VERSION 5.8 ;
BUSBITCHARS "[]" ;
DIVIDERCHAR "/" ;
UNITS
    DATABASE MICRONS 1000 ;
END UNITS

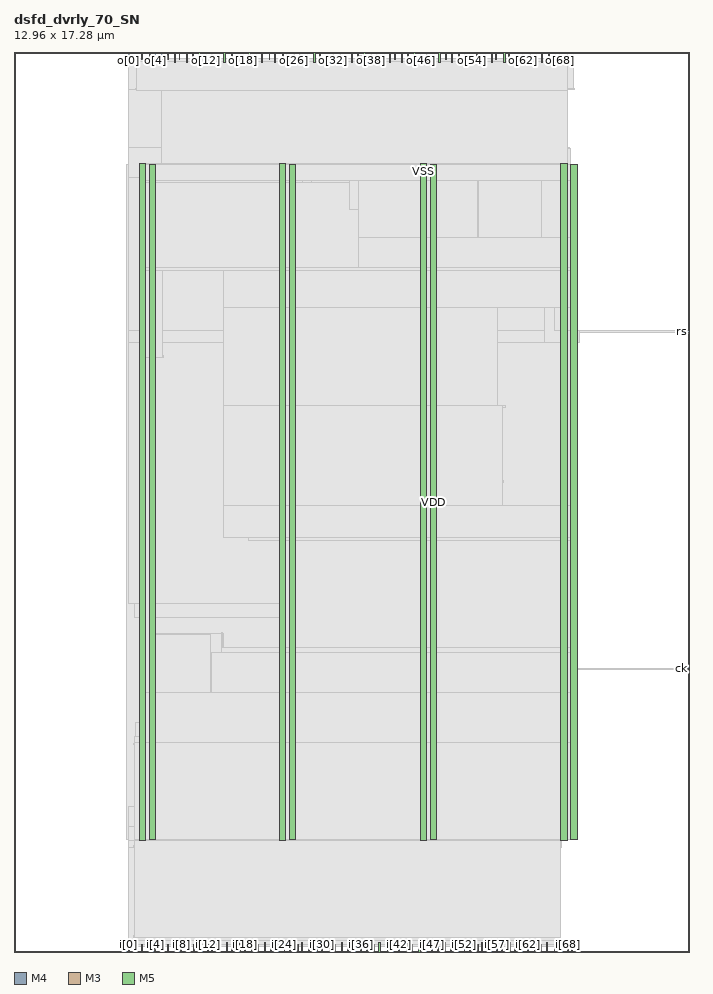
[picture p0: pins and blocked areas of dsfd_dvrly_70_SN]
MACRO dsfd_dvrly_70_SN
  FOREIGN dsfd_dvrly_70_SN 0 0 ;
  CLASS BLOCK ;
  SIZE 12.96 BY 17.28 ;
  PIN ck
    DIRECTION INPUT ;
    USE SIGNAL ;
    PORT
      LAYER M4 ;
        RECT  12.768 5.424 12.96 5.448 ;
    END
  END ck
  PIN ck_o
    DIRECTION OUTPUT ;
    USE SIGNAL ;
    PORT
      LAYER M3 ;
        RECT  10.728 17.136 10.746 17.28 ;
    END
  END ck_o
  PIN i[0]
    DIRECTION INPUT ;
    USE SIGNAL ;
    PORT
      LAYER M3 ;
        RECT  2.196 0 2.214 0.144 ;
    END
  END i[0]
  PIN i[10]
    DIRECTION INPUT ;
    USE SIGNAL ;
    PORT
      LAYER M3 ;
        RECT  3.456 0 3.474 0.144 ;
    END
  END i[10]
  PIN i[11]
    DIRECTION INPUT ;
    USE SIGNAL ;
    PORT
      LAYER M5 ;
        RECT  3.552 0 3.576 0.192 ;
    END
  END i[11]
  PIN i[12]
    DIRECTION INPUT ;
    USE SIGNAL ;
    PORT
      LAYER M3 ;
        RECT  3.708 0 3.726 0.144 ;
    END
  END i[12]
  PIN i[13]
    DIRECTION INPUT ;
    USE SIGNAL ;
    PORT
      LAYER M5 ;
        RECT  3.792 0 3.816 0.192 ;
    END
  END i[13]
  PIN i[14]
    DIRECTION INPUT ;
    USE SIGNAL ;
    PORT
      LAYER M3 ;
        RECT  3.924 0 3.942 0.144 ;
    END
  END i[14]
  PIN i[15]
    DIRECTION INPUT ;
    USE SIGNAL ;
    PORT
      LAYER M5 ;
        RECT  4.08 0 4.104 0.192 ;
    END
  END i[15]
  PIN i[16]
    DIRECTION INPUT ;
    USE SIGNAL ;
    PORT
      LAYER M3 ;
        RECT  4.176 0 4.194 0.144 ;
    END
  END i[16]
  PIN i[17]
    DIRECTION INPUT ;
    USE SIGNAL ;
    PORT
      LAYER M5 ;
        RECT  4.32 0 4.344 0.192 ;
    END
  END i[17]
  PIN i[18]
    DIRECTION INPUT ;
    USE SIGNAL ;
    PORT
      LAYER M3 ;
        RECT  4.428 0 4.446 0.144 ;
    END
  END i[18]
  PIN i[19]
    DIRECTION INPUT ;
    USE SIGNAL ;
    PORT
      LAYER M5 ;
        RECT  4.56 0 4.584 0.192 ;
    END
  END i[19]
  PIN i[1]
    DIRECTION INPUT ;
    USE SIGNAL ;
    PORT
      LAYER M5 ;
        RECT  2.352 0 2.376 0.192 ;
    END
  END i[1]
  PIN i[20]
    DIRECTION INPUT ;
    USE SIGNAL ;
    PORT
      LAYER M3 ;
        RECT  4.68 0 4.698 0.144 ;
    END
  END i[20]
  PIN i[21]
    DIRECTION INPUT ;
    USE SIGNAL ;
    PORT
      LAYER M5 ;
        RECT  4.8 0 4.824 0.192 ;
    END
  END i[21]
  PIN i[22]
    DIRECTION INPUT ;
    USE SIGNAL ;
    PORT
      LAYER M3 ;
        RECT  4.932 0 4.95 0.144 ;
    END
  END i[22]
  PIN i[23]
    DIRECTION INPUT ;
    USE SIGNAL ;
    PORT
      LAYER M5 ;
        RECT  5.04 0 5.064 0.192 ;
    END
  END i[23]
  PIN i[24]
    DIRECTION INPUT ;
    USE SIGNAL ;
    PORT
      LAYER M3 ;
        RECT  5.184 0 5.202 0.144 ;
    END
  END i[24]
  PIN i[25]
    DIRECTION INPUT ;
    USE SIGNAL ;
    PORT
      LAYER M5 ;
        RECT  5.28 0 5.304 0.192 ;
    END
  END i[25]
  PIN i[26]
    DIRECTION INPUT ;
    USE SIGNAL ;
    PORT
      LAYER M3 ;
        RECT  5.436 0 5.454 0.144 ;
    END
  END i[26]
  PIN i[27]
    DIRECTION INPUT ;
    USE SIGNAL ;
    PORT
      LAYER M5 ;
        RECT  5.52 0 5.544 0.192 ;
    END
  END i[27]
  PIN i[28]
    DIRECTION INPUT ;
    USE SIGNAL ;
    PORT
      LAYER M3 ;
        RECT  5.652 0 5.67 0.144 ;
    END
  END i[28]
  PIN i[29]
    DIRECTION INPUT ;
    USE SIGNAL ;
    PORT
      LAYER M5 ;
        RECT  5.808 0 5.832 0.192 ;
    END
  END i[29]
  PIN i[2]
    DIRECTION INPUT ;
    USE SIGNAL ;
    PORT
      LAYER M3 ;
        RECT  2.448 0 2.466 0.144 ;
    END
  END i[2]
  PIN i[30]
    DIRECTION INPUT ;
    USE SIGNAL ;
    PORT
      LAYER M3 ;
        RECT  5.904 0 5.922 0.144 ;
    END
  END i[30]
  PIN i[31]
    DIRECTION INPUT ;
    USE SIGNAL ;
    PORT
      LAYER M5 ;
        RECT  6.048 0 6.072 0.192 ;
    END
  END i[31]
  PIN i[32]
    DIRECTION INPUT ;
    USE SIGNAL ;
    PORT
      LAYER M3 ;
        RECT  6.156 0 6.174 0.144 ;
    END
  END i[32]
  PIN i[33]
    DIRECTION INPUT ;
    USE SIGNAL ;
    PORT
      LAYER M5 ;
        RECT  6.288 0 6.312 0.192 ;
    END
  END i[33]
  PIN i[34]
    DIRECTION INPUT ;
    USE SIGNAL ;
    PORT
      LAYER M3 ;
        RECT  6.408 0 6.426 0.144 ;
    END
  END i[34]
  PIN i[35]
    DIRECTION INPUT ;
    USE SIGNAL ;
    PORT
      LAYER M5 ;
        RECT  6.528 0 6.552 0.192 ;
    END
  END i[35]
  PIN i[36]
    DIRECTION INPUT ;
    USE SIGNAL ;
    PORT
      LAYER M3 ;
        RECT  6.66 0 6.678 0.144 ;
    END
  END i[36]
  PIN i[37]
    DIRECTION INPUT ;
    USE SIGNAL ;
    PORT
      LAYER M5 ;
        RECT  6.768 0 6.792 0.192 ;
    END
  END i[37]
  PIN i[38]
    DIRECTION INPUT ;
    USE SIGNAL ;
    PORT
      LAYER M3 ;
        RECT  6.912 0 6.93 0.144 ;
    END
  END i[38]
  PIN i[39]
    DIRECTION INPUT ;
    USE SIGNAL ;
    PORT
      LAYER M5 ;
        RECT  7.008 0 7.032 0.192 ;
    END
  END i[39]
  PIN i[3]
    DIRECTION INPUT ;
    USE SIGNAL ;
    PORT
      LAYER M5 ;
        RECT  2.592 0 2.616 0.192 ;
    END
  END i[3]
  PIN i[40]
    DIRECTION INPUT ;
    USE SIGNAL ;
    PORT
      LAYER M3 ;
        RECT  7.164 0 7.182 0.144 ;
    END
  END i[40]
  PIN i[41]
    DIRECTION INPUT ;
    USE SIGNAL ;
    PORT
      LAYER M5 ;
        RECT  7.248 0 7.272 0.192 ;
    END
  END i[41]
  PIN i[42]
    DIRECTION INPUT ;
    USE SIGNAL ;
    PORT
      LAYER M3 ;
        RECT  7.38 0 7.398 0.144 ;
    END
  END i[42]
  PIN i[43]
    DIRECTION INPUT ;
    USE SIGNAL ;
    PORT
      LAYER M5 ;
        RECT  7.536 0 7.56 0.192 ;
    END
  END i[43]
  PIN i[44]
    DIRECTION INPUT ;
    USE SIGNAL ;
    PORT
      LAYER M3 ;
        RECT  7.632 0 7.65 0.144 ;
    END
  END i[44]
  PIN i[45]
    DIRECTION INPUT ;
    USE SIGNAL ;
    PORT
      LAYER M5 ;
        RECT  7.776 0 7.8 0.192 ;
    END
  END i[45]
  PIN i[46]
    DIRECTION INPUT ;
    USE SIGNAL ;
    PORT
      LAYER M3 ;
        RECT  7.884 0 7.902 0.144 ;
    END
  END i[46]
  PIN i[47]
    DIRECTION INPUT ;
    USE SIGNAL ;
    PORT
      LAYER M5 ;
        RECT  8.016 0 8.04 0.192 ;
    END
  END i[47]
  PIN i[48]
    DIRECTION INPUT ;
    USE SIGNAL ;
    PORT
      LAYER M3 ;
        RECT  8.136 0 8.154 0.144 ;
    END
  END i[48]
  PIN i[49]
    DIRECTION INPUT ;
    USE SIGNAL ;
    PORT
      LAYER M5 ;
        RECT  8.256 0 8.28 0.192 ;
    END
  END i[49]
  PIN i[4]
    DIRECTION INPUT ;
    USE SIGNAL ;
    PORT
      LAYER M3 ;
        RECT  2.7 0 2.718 0.144 ;
    END
  END i[4]
  PIN i[50]
    DIRECTION INPUT ;
    USE SIGNAL ;
    PORT
      LAYER M3 ;
        RECT  8.388 0 8.406 0.144 ;
    END
  END i[50]
  PIN i[51]
    DIRECTION INPUT ;
    USE SIGNAL ;
    PORT
      LAYER M5 ;
        RECT  8.496 0 8.52 0.192 ;
    END
  END i[51]
  PIN i[52]
    DIRECTION INPUT ;
    USE SIGNAL ;
    PORT
      LAYER M3 ;
        RECT  8.64 0 8.658 0.144 ;
    END
  END i[52]
  PIN i[53]
    DIRECTION INPUT ;
    USE SIGNAL ;
    PORT
      LAYER M5 ;
        RECT  8.736 0 8.76 0.192 ;
    END
  END i[53]
  PIN i[54]
    DIRECTION INPUT ;
    USE SIGNAL ;
    PORT
      LAYER M3 ;
        RECT  8.892 0 8.91 0.144 ;
    END
  END i[54]
  PIN i[55]
    DIRECTION INPUT ;
    USE SIGNAL ;
    PORT
      LAYER M5 ;
        RECT  8.976 0 9 0.192 ;
    END
  END i[55]
  PIN i[56]
    DIRECTION INPUT ;
    USE SIGNAL ;
    PORT
      LAYER M3 ;
        RECT  9.108 0 9.126 0.144 ;
    END
  END i[56]
  PIN i[57]
    DIRECTION INPUT ;
    USE SIGNAL ;
    PORT
      LAYER M5 ;
        RECT  9.264 0 9.288 0.192 ;
    END
  END i[57]
  PIN i[58]
    DIRECTION INPUT ;
    USE SIGNAL ;
    PORT
      LAYER M3 ;
        RECT  9.36 0 9.378 0.144 ;
    END
  END i[58]
  PIN i[59]
    DIRECTION INPUT ;
    USE SIGNAL ;
    PORT
      LAYER M5 ;
        RECT  9.504 0 9.528 0.192 ;
    END
  END i[59]
  PIN i[5]
    DIRECTION INPUT ;
    USE SIGNAL ;
    PORT
      LAYER M5 ;
        RECT  2.832 0 2.856 0.192 ;
    END
  END i[5]
  PIN i[60]
    DIRECTION INPUT ;
    USE SIGNAL ;
    PORT
      LAYER M3 ;
        RECT  9.612 0 9.63 0.144 ;
    END
  END i[60]
  PIN i[61]
    DIRECTION INPUT ;
    USE SIGNAL ;
    PORT
      LAYER M5 ;
        RECT  9.744 0 9.768 0.192 ;
    END
  END i[61]
  PIN i[62]
    DIRECTION INPUT ;
    USE SIGNAL ;
    PORT
      LAYER M3 ;
        RECT  9.864 0 9.882 0.144 ;
    END
  END i[62]
  PIN i[63]
    DIRECTION INPUT ;
    USE SIGNAL ;
    PORT
      LAYER M5 ;
        RECT  9.984 0 10.008 0.192 ;
    END
  END i[63]
  PIN i[64]
    DIRECTION INPUT ;
    USE SIGNAL ;
    PORT
      LAYER M3 ;
        RECT  10.116 0 10.134 0.144 ;
    END
  END i[64]
  PIN i[65]
    DIRECTION INPUT ;
    USE SIGNAL ;
    PORT
      LAYER M5 ;
        RECT  10.224 0 10.248 0.192 ;
    END
  END i[65]
  PIN i[66]
    DIRECTION INPUT ;
    USE SIGNAL ;
    PORT
      LAYER M3 ;
        RECT  10.368 0 10.386 0.144 ;
    END
  END i[66]
  PIN i[67]
    DIRECTION INPUT ;
    USE SIGNAL ;
    PORT
      LAYER M5 ;
        RECT  10.464 0 10.488 0.192 ;
    END
  END i[67]
  PIN i[68]
    DIRECTION INPUT ;
    USE SIGNAL ;
    PORT
      LAYER M3 ;
        RECT  10.62 0 10.638 0.144 ;
    END
  END i[68]
  PIN i[69]
    DIRECTION INPUT ;
    USE SIGNAL ;
    PORT
      LAYER M5 ;
        RECT  10.704 0 10.728 0.192 ;
    END
  END i[69]
  PIN i[6]
    DIRECTION INPUT ;
    USE SIGNAL ;
    PORT
      LAYER M3 ;
        RECT  2.952 0 2.97 0.144 ;
    END
  END i[6]
  PIN i[7]
    DIRECTION INPUT ;
    USE SIGNAL ;
    PORT
      LAYER M5 ;
        RECT  3.072 0 3.096 0.192 ;
    END
  END i[7]
  PIN i[8]
    DIRECTION INPUT ;
    USE SIGNAL ;
    PORT
      LAYER M3 ;
        RECT  3.204 0 3.222 0.144 ;
    END
  END i[8]
  PIN i[9]
    DIRECTION INPUT ;
    USE SIGNAL ;
    PORT
      LAYER M5 ;
        RECT  3.312 0 3.336 0.192 ;
    END
  END i[9]
  PIN o[0]
    DIRECTION OUTPUT ;
    USE SIGNAL ;
    PORT
      LAYER M3 ;
        RECT  2.196 17.136 2.214 17.28 ;
    END
  END o[0]
  PIN o[10]
    DIRECTION OUTPUT ;
    USE SIGNAL ;
    PORT
      LAYER M3 ;
        RECT  3.42 17.136 3.438 17.28 ;
    END
  END o[10]
  PIN o[11]
    DIRECTION OUTPUT ;
    USE SIGNAL ;
    PORT
      LAYER M5 ;
        RECT  3.552 17.088 3.576 17.28 ;
    END
  END o[11]
  PIN o[12]
    DIRECTION OUTPUT ;
    USE SIGNAL ;
    PORT
      LAYER M3 ;
        RECT  3.672 17.136 3.69 17.28 ;
    END
  END o[12]
  PIN o[13]
    DIRECTION OUTPUT ;
    USE SIGNAL ;
    PORT
      LAYER M5 ;
        RECT  3.792 17.088 3.816 17.28 ;
    END
  END o[13]
  PIN o[14]
    DIRECTION OUTPUT ;
    USE SIGNAL ;
    PORT
      LAYER M3 ;
        RECT  3.924 17.136 3.942 17.28 ;
    END
  END o[14]
  PIN o[15]
    DIRECTION OUTPUT ;
    USE SIGNAL ;
    PORT
      LAYER M5 ;
        RECT  4.032 17.088 4.056 17.28 ;
    END
  END o[15]
  PIN o[16]
    DIRECTION OUTPUT ;
    USE SIGNAL ;
    PORT
      LAYER M3 ;
        RECT  4.176 17.136 4.194 17.28 ;
    END
  END o[16]
  PIN o[17]
    DIRECTION OUTPUT ;
    USE SIGNAL ;
    PORT
      LAYER M5 ;
        RECT  4.272 17.088 4.296 17.28 ;
    END
  END o[17]
  PIN o[18]
    DIRECTION OUTPUT ;
    USE SIGNAL ;
    PORT
      LAYER M3 ;
        RECT  4.392 17.136 4.41 17.28 ;
    END
  END o[18]
  PIN o[19]
    DIRECTION OUTPUT ;
    USE SIGNAL ;
    PORT
      LAYER M5 ;
        RECT  4.512 17.088 4.536 17.28 ;
    END
  END o[19]
  PIN o[1]
    DIRECTION OUTPUT ;
    USE SIGNAL ;
    PORT
      LAYER M5 ;
        RECT  2.352 17.088 2.376 17.28 ;
    END
  END o[1]
  PIN o[20]
    DIRECTION OUTPUT ;
    USE SIGNAL ;
    PORT
      LAYER M3 ;
        RECT  4.644 17.136 4.662 17.28 ;
    END
  END o[20]
  PIN o[21]
    DIRECTION OUTPUT ;
    USE SIGNAL ;
    PORT
      LAYER M5 ;
        RECT  4.752 17.088 4.776 17.28 ;
    END
  END o[21]
  PIN o[22]
    DIRECTION OUTPUT ;
    USE SIGNAL ;
    PORT
      LAYER M3 ;
        RECT  4.896 17.136 4.914 17.28 ;
    END
  END o[22]
  PIN o[23]
    DIRECTION OUTPUT ;
    USE SIGNAL ;
    PORT
      LAYER M5 ;
        RECT  4.992 17.088 5.016 17.28 ;
    END
  END o[23]
  PIN o[24]
    DIRECTION OUTPUT ;
    USE SIGNAL ;
    PORT
      LAYER M3 ;
        RECT  5.148 17.136 5.166 17.28 ;
    END
  END o[24]
  PIN o[25]
    DIRECTION OUTPUT ;
    USE SIGNAL ;
    PORT
      LAYER M5 ;
        RECT  5.232 17.088 5.256 17.28 ;
    END
  END o[25]
  PIN o[26]
    DIRECTION OUTPUT ;
    USE SIGNAL ;
    PORT
      LAYER M3 ;
        RECT  5.364 17.136 5.382 17.28 ;
    END
  END o[26]
  PIN o[27]
    DIRECTION OUTPUT ;
    USE SIGNAL ;
    PORT
      LAYER M5 ;
        RECT  5.472 17.088 5.496 17.28 ;
    END
  END o[27]
  PIN o[28]
    DIRECTION OUTPUT ;
    USE SIGNAL ;
    PORT
      LAYER M3 ;
        RECT  5.616 17.136 5.634 17.28 ;
    END
  END o[28]
  PIN o[29]
    DIRECTION OUTPUT ;
    USE SIGNAL ;
    PORT
      LAYER M5 ;
        RECT  5.76 17.088 5.784 17.28 ;
    END
  END o[29]
  PIN o[2]
    DIRECTION OUTPUT ;
    USE SIGNAL ;
    PORT
      LAYER M3 ;
        RECT  2.448 17.136 2.466 17.28 ;
    END
  END o[2]
  PIN o[30]
    DIRECTION OUTPUT ;
    USE SIGNAL ;
    PORT
      LAYER M3 ;
        RECT  5.868 17.136 5.886 17.28 ;
    END
  END o[30]
  PIN o[31]
    DIRECTION OUTPUT ;
    USE SIGNAL ;
    PORT
      LAYER M5 ;
        RECT  6 17.088 6.024 17.28 ;
    END
  END o[31]
  PIN o[32]
    DIRECTION OUTPUT ;
    USE SIGNAL ;
    PORT
      LAYER M3 ;
        RECT  6.12 17.136 6.138 17.28 ;
    END
  END o[32]
  PIN o[33]
    DIRECTION OUTPUT ;
    USE SIGNAL ;
    PORT
      LAYER M5 ;
        RECT  6.24 17.088 6.264 17.28 ;
    END
  END o[33]
  PIN o[34]
    DIRECTION OUTPUT ;
    USE SIGNAL ;
    PORT
      LAYER M3 ;
        RECT  6.336 17.136 6.354 17.28 ;
    END
  END o[34]
  PIN o[35]
    DIRECTION OUTPUT ;
    USE SIGNAL ;
    PORT
      LAYER M5 ;
        RECT  6.48 17.088 6.504 17.28 ;
    END
  END o[35]
  PIN o[36]
    DIRECTION OUTPUT ;
    USE SIGNAL ;
    PORT
      LAYER M3 ;
        RECT  6.588 17.136 6.606 17.28 ;
    END
  END o[36]
  PIN o[37]
    DIRECTION OUTPUT ;
    USE SIGNAL ;
    PORT
      LAYER M5 ;
        RECT  6.72 17.088 6.744 17.28 ;
    END
  END o[37]
  PIN o[38]
    DIRECTION OUTPUT ;
    USE SIGNAL ;
    PORT
      LAYER M3 ;
        RECT  6.84 17.136 6.858 17.28 ;
    END
  END o[38]
  PIN o[39]
    DIRECTION OUTPUT ;
    USE SIGNAL ;
    PORT
      LAYER M5 ;
        RECT  6.96 17.088 6.984 17.28 ;
    END
  END o[39]
  PIN o[3]
    DIRECTION OUTPUT ;
    USE SIGNAL ;
    PORT
      LAYER M5 ;
        RECT  2.592 17.088 2.616 17.28 ;
    END
  END o[3]
  PIN o[40]
    DIRECTION OUTPUT ;
    USE SIGNAL ;
    PORT
      LAYER M3 ;
        RECT  7.092 17.136 7.11 17.28 ;
    END
  END o[40]
  PIN o[41]
    DIRECTION OUTPUT ;
    USE SIGNAL ;
    PORT
      LAYER M5 ;
        RECT  7.2 17.088 7.224 17.28 ;
    END
  END o[41]
  PIN o[42]
    DIRECTION OUTPUT ;
    USE SIGNAL ;
    PORT
      LAYER M3 ;
        RECT  7.308 17.136 7.326 17.28 ;
    END
  END o[42]
  PIN o[43]
    DIRECTION OUTPUT ;
    USE SIGNAL ;
    PORT
      LAYER M5 ;
        RECT  7.44 17.088 7.464 17.28 ;
    END
  END o[43]
  PIN o[44]
    DIRECTION OUTPUT ;
    USE SIGNAL ;
    PORT
      LAYER M3 ;
        RECT  7.56 17.136 7.578 17.28 ;
    END
  END o[44]
  PIN o[45]
    DIRECTION OUTPUT ;
    USE SIGNAL ;
    PORT
      LAYER M5 ;
        RECT  7.68 17.088 7.704 17.28 ;
    END
  END o[45]
  PIN o[46]
    DIRECTION OUTPUT ;
    USE SIGNAL ;
    PORT
      LAYER M3 ;
        RECT  7.812 17.136 7.83 17.28 ;
    END
  END o[46]
  PIN o[47]
    DIRECTION OUTPUT ;
    USE SIGNAL ;
    PORT
      LAYER M5 ;
        RECT  7.92 17.088 7.944 17.28 ;
    END
  END o[47]
  PIN o[48]
    DIRECTION OUTPUT ;
    USE SIGNAL ;
    PORT
      LAYER M3 ;
        RECT  8.064 17.136 8.082 17.28 ;
    END
  END o[48]
  PIN o[49]
    DIRECTION OUTPUT ;
    USE SIGNAL ;
    PORT
      LAYER M5 ;
        RECT  8.16 17.088 8.184 17.28 ;
    END
  END o[49]
  PIN o[4]
    DIRECTION OUTPUT ;
    USE SIGNAL ;
    PORT
      LAYER M3 ;
        RECT  2.7 17.136 2.718 17.28 ;
    END
  END o[4]
  PIN o[50]
    DIRECTION OUTPUT ;
    USE SIGNAL ;
    PORT
      LAYER M3 ;
        RECT  8.28 17.136 8.298 17.28 ;
    END
  END o[50]
  PIN o[51]
    DIRECTION OUTPUT ;
    USE SIGNAL ;
    PORT
      LAYER M5 ;
        RECT  8.4 17.088 8.424 17.28 ;
    END
  END o[51]
  PIN o[52]
    DIRECTION OUTPUT ;
    USE SIGNAL ;
    PORT
      LAYER M3 ;
        RECT  8.532 17.136 8.55 17.28 ;
    END
  END o[52]
  PIN o[53]
    DIRECTION OUTPUT ;
    USE SIGNAL ;
    PORT
      LAYER M5 ;
        RECT  8.64 17.088 8.664 17.28 ;
    END
  END o[53]
  PIN o[54]
    DIRECTION OUTPUT ;
    USE SIGNAL ;
    PORT
      LAYER M3 ;
        RECT  8.784 17.136 8.802 17.28 ;
    END
  END o[54]
  PIN o[55]
    DIRECTION OUTPUT ;
    USE SIGNAL ;
    PORT
      LAYER M5 ;
        RECT  8.88 17.088 8.904 17.28 ;
    END
  END o[55]
  PIN o[56]
    DIRECTION OUTPUT ;
    USE SIGNAL ;
    PORT
      LAYER M3 ;
        RECT  9.036 17.136 9.054 17.28 ;
    END
  END o[56]
  PIN o[57]
    DIRECTION OUTPUT ;
    USE SIGNAL ;
    PORT
      LAYER M5 ;
        RECT  9.168 17.088 9.192 17.28 ;
    END
  END o[57]
  PIN o[58]
    DIRECTION OUTPUT ;
    USE SIGNAL ;
    PORT
      LAYER M3 ;
        RECT  9.252 17.136 9.27 17.28 ;
    END
  END o[58]
  PIN o[59]
    DIRECTION OUTPUT ;
    USE SIGNAL ;
    PORT
      LAYER M5 ;
        RECT  9.408 17.088 9.432 17.28 ;
    END
  END o[59]
  PIN o[5]
    DIRECTION OUTPUT ;
    USE SIGNAL ;
    PORT
      LAYER M5 ;
        RECT  2.832 17.088 2.856 17.28 ;
    END
  END o[5]
  PIN o[60]
    DIRECTION OUTPUT ;
    USE SIGNAL ;
    PORT
      LAYER M3 ;
        RECT  9.504 17.136 9.522 17.28 ;
    END
  END o[60]
  PIN o[61]
    DIRECTION OUTPUT ;
    USE SIGNAL ;
    PORT
      LAYER M5 ;
        RECT  9.648 17.088 9.672 17.28 ;
    END
  END o[61]
  PIN o[62]
    DIRECTION OUTPUT ;
    USE SIGNAL ;
    PORT
      LAYER M3 ;
        RECT  9.756 17.136 9.774 17.28 ;
    END
  END o[62]
  PIN o[63]
    DIRECTION OUTPUT ;
    USE SIGNAL ;
    PORT
      LAYER M5 ;
        RECT  9.888 17.088 9.912 17.28 ;
    END
  END o[63]
  PIN o[64]
    DIRECTION OUTPUT ;
    USE SIGNAL ;
    PORT
      LAYER M3 ;
        RECT  10.008 17.136 10.026 17.28 ;
    END
  END o[64]
  PIN o[65]
    DIRECTION OUTPUT ;
    USE SIGNAL ;
    PORT
      LAYER M5 ;
        RECT  10.128 17.088 10.152 17.28 ;
    END
  END o[65]
  PIN o[66]
    DIRECTION OUTPUT ;
    USE SIGNAL ;
    PORT
      LAYER M3 ;
        RECT  10.26 17.136 10.278 17.28 ;
    END
  END o[66]
  PIN o[67]
    DIRECTION OUTPUT ;
    USE SIGNAL ;
    PORT
      LAYER M5 ;
        RECT  10.368 17.088 10.392 17.28 ;
    END
  END o[67]
  PIN o[68]
    DIRECTION OUTPUT ;
    USE SIGNAL ;
    PORT
      LAYER M3 ;
        RECT  10.476 17.136 10.494 17.28 ;
    END
  END o[68]
  PIN o[69]
    DIRECTION OUTPUT ;
    USE SIGNAL ;
    PORT
      LAYER M5 ;
        RECT  10.608 17.088 10.632 17.28 ;
    END
  END o[69]
  PIN o[6]
    DIRECTION OUTPUT ;
    USE SIGNAL ;
    PORT
      LAYER M3 ;
        RECT  2.952 17.136 2.97 17.28 ;
    END
  END o[6]
  PIN o[7]
    DIRECTION OUTPUT ;
    USE SIGNAL ;
    PORT
      LAYER M5 ;
        RECT  3.072 17.088 3.096 17.28 ;
    END
  END o[7]
  PIN o[8]
    DIRECTION OUTPUT ;
    USE SIGNAL ;
    PORT
      LAYER M3 ;
        RECT  3.168 17.136 3.186 17.28 ;
    END
  END o[8]
  PIN o[9]
    DIRECTION OUTPUT ;
    USE SIGNAL ;
    PORT
      LAYER M5 ;
        RECT  3.312 17.088 3.336 17.28 ;
    END
  END o[9]
  PIN rs
    DIRECTION INPUT ;
    USE SIGNAL ;
    PORT
      LAYER M4 ;
        RECT  12.768 11.904 12.96 11.928 ;
    END
  END rs
  PIN VDD
    DIRECTION INOUT ;
    USE POWER ;
    PORT
      LAYER M5 ;
        RECT  10.692 2.151 10.812 15.129 ;
        RECT  7.992 2.151 8.112 15.129 ;
        RECT  5.292 2.151 5.412 15.129 ;
        RECT  2.592 2.151 2.712 15.129 ;
    END
  END VDD
  PIN VSS
    DIRECTION INOUT ;
    USE GROUND ;
    PORT
      LAYER M5 ;
        RECT  10.5 2.137 10.62 15.143 ;
        RECT  7.8 2.137 7.92 15.143 ;
        RECT  5.1 2.137 5.22 15.143 ;
        RECT  2.4 2.137 2.52 15.143 ;
    END
  END VSS
  OBS
    LAYER RVTN ;
     RECT  2.16 2.16 10.8 2.295 ;
     RECT  2.16 2.565 10.8 2.835 ;
     RECT  2.16 3.105 10.8 3.375 ;
     RECT  2.16 3.645 10.8 3.915 ;
     RECT  2.16 4.185 10.8 4.455 ;
     RECT  2.16 4.725 10.8 4.995 ;
     RECT  2.16 5.265 10.8 5.535 ;
     RECT  2.16 5.805 10.8 6.075 ;
     RECT  2.16 6.345 10.8 6.615 ;
     RECT  2.16 6.885 10.8 7.155 ;
     RECT  2.16 7.425 10.8 7.695 ;
     RECT  2.16 7.965 10.8 8.235 ;
     RECT  2.16 8.505 10.8 8.775 ;
     RECT  2.16 9.045 10.8 9.315 ;
     RECT  2.16 9.585 10.8 9.855 ;
     RECT  2.16 10.125 10.8 10.395 ;
     RECT  2.16 10.665 10.8 10.935 ;
     RECT  2.16 11.205 10.8 11.475 ;
     RECT  2.16 11.745 10.8 12.015 ;
     RECT  2.16 12.285 10.8 12.555 ;
     RECT  2.16 12.825 10.8 13.095 ;
     RECT  2.16 13.365 10.8 13.635 ;
     RECT  2.16 13.905 10.8 14.175 ;
     RECT  2.16 14.445 10.8 14.715 ;
     RECT  2.16 14.985 10.8 15.12 ;
    LAYER RVTP ;
     RECT  2.16 2.295 10.8 2.565 ;
     RECT  2.16 2.835 10.8 3.105 ;
     RECT  2.16 3.375 10.8 3.645 ;
     RECT  2.16 3.915 10.8 4.185 ;
     RECT  2.16 4.455 10.8 4.725 ;
     RECT  2.16 4.995 10.8 5.265 ;
     RECT  2.16 5.535 10.8 5.805 ;
     RECT  2.16 6.075 10.8 6.345 ;
     RECT  2.16 6.615 10.8 6.885 ;
     RECT  2.16 7.155 10.8 7.425 ;
     RECT  2.16 7.695 10.8 7.965 ;
     RECT  2.16 8.235 10.8 8.505 ;
     RECT  2.16 8.775 10.8 9.045 ;
     RECT  2.16 9.315 10.8 9.585 ;
     RECT  2.16 9.855 10.8 10.125 ;
     RECT  2.16 10.395 10.8 10.665 ;
     RECT  2.16 10.935 10.8 11.205 ;
     RECT  2.16 11.475 10.8 11.745 ;
     RECT  2.16 12.015 10.8 12.285 ;
     RECT  2.16 12.555 10.8 12.825 ;
     RECT  2.16 13.095 10.8 13.365 ;
     RECT  2.16 13.635 10.8 13.905 ;
     RECT  2.16 14.175 10.8 14.445 ;
     RECT  2.16 14.715 10.8 14.985 ;
    LAYER M1 ;
     RECT  2.16 2.151 10.8 15.129 ;
    LAYER M2 ;
     RECT  2.443 16.542 2.695 16.56 ;
     RECT  2.299 0.144 2.795 0.162 ;
     RECT  2.695 16.542 3.299 16.596 ;
     RECT  3.523 0.216 3.703 0.234 ;
     RECT  3.703 0.144 3.947 0.234 ;
     RECT  3.947 0.144 3.983 0.162 ;
     RECT  3.299 16.542 4.271 16.56 ;
     RECT  2.16 2.151 4.819 15.129 ;
     RECT  4.819 2.106 5.099 15.129 ;
     RECT  5.099 2.151 5.143 15.129 ;
     RECT  5.179 0.144 5.279 0.162 ;
     RECT  5.143 2.151 5.279 15.21 ;
     RECT  5.359 16.542 6.071 16.56 ;
     RECT  6.583 17.118 6.619 17.136 ;
     RECT  6.619 17.118 6.719 17.208 ;
     RECT  5.279 2.151 7.087 15.129 ;
     RECT  7.087 2.151 7.483 15.174 ;
     RECT  7.483 2.106 7.807 15.174 ;
     RECT  6.403 0.144 7.979 0.162 ;
     RECT  7.807 2.106 7.979 15.21 ;
     RECT  7.979 2.106 10.103 15.174 ;
     RECT  10.103 2.151 10.391 15.174 ;
     RECT  9.355 0.144 10.643 0.162 ;
     RECT  10.391 2.151 10.8 15.129 ;
     RECT  10.8 2.421 10.812 14.859 ;
    LAYER M3 ;
     RECT  2.196 0.108 10.638 0.167 ;
     RECT  2.196 0.167 10.422 2.011 ;
     RECT  2.196 2.011 10.494 2.143 ;
     RECT  2.196 2.143 10.605 2.413 ;
     RECT  2.196 2.413 10.797 2.795 ;
     RECT  2.304 2.795 10.797 4.145 ;
     RECT  2.34 4.145 10.797 4.415 ;
     RECT  2.415 4.415 10.797 6.421 ;
     RECT  2.304 6.421 10.797 6.691 ;
     RECT  2.196 6.691 10.797 11.707 ;
     RECT  2.196 11.707 10.854 11.933 ;
     RECT  2.196 11.933 10.797 14.867 ;
     RECT  2.196 14.867 10.674 15.437 ;
     RECT  2.196 15.437 10.494 16.555 ;
     RECT  2.196 16.555 10.746 17.148 ;
     RECT  6.624 17.148 6.714 17.213 ;
    LAYER M4 ;
     RECT  2.3 2.016 2.365 2.04 ;
     RECT  2.365 2.016 2.408 2.28 ;
     RECT  2.285 3.984 2.408 4.008 ;
     RECT  2.408 2.016 2.512 15.132 ;
     RECT  2.341 16.56 2.581 16.584 ;
     RECT  2.293 0.288 2.627 0.312 ;
     RECT  2.512 2.016 2.704 14.862 ;
     RECT  2.704 11.424 2.867 11.448 ;
     RECT  2.704 2.016 3.293 3.288 ;
     RECT  2.581 16.56 3.301 16.632 ;
     RECT  3.301 16.56 3.629 16.68 ;
     RECT  2.704 4.464 3.683 4.968 ;
     RECT  3.629 16.656 3.737 16.68 ;
     RECT  3.293 1.728 3.769 3.288 ;
     RECT  3.683 4.944 3.781 4.968 ;
     RECT  2.704 6.096 3.781 6.12 ;
     RECT  3.769 1.728 3.853 3.96 ;
     RECT  3.781 4.944 4.019 6.12 ;
     RECT  4.019 4.944 4.061 5.832 ;
     RECT  4.021 7.968 4.501 7.992 ;
     RECT  4.261 9.072 4.981 9.096 ;
     RECT  3.853 1.728 5.108 3.432 ;
     RECT  4.061 4.992 5.108 5.832 ;
     RECT  4.501 7.92 5.108 7.992 ;
     RECT  4.981 9.024 5.108 9.096 ;
     RECT  3.781 13.104 5.108 13.128 ;
     RECT  4.741 14.832 5.108 14.856 ;
     RECT  5.108 1.728 5.221 15.132 ;
     RECT  5.221 1.728 5.404 15.288 ;
     RECT  5.404 14.784 5.461 15.288 ;
     RECT  5.404 9.024 5.501 9.096 ;
     RECT  5.404 1.728 5.537 2.904 ;
     RECT  5.537 2.256 5.609 2.904 ;
     RECT  5.461 14.784 5.717 15.384 ;
     RECT  5.404 3.936 5.825 7.944 ;
     RECT  5.404 13.104 5.941 13.128 ;
     RECT  6.145 0.144 6.421 0.168 ;
     RECT  5.717 14.784 6.433 15.096 ;
     RECT  5.825 3.936 6.541 7.128 ;
     RECT  6.421 0.144 6.563 0.216 ;
     RECT  5.609 2.256 6.613 2.712 ;
     RECT  6.433 14.256 6.659 15.096 ;
     RECT  6.563 0.144 6.707 0.168 ;
     RECT  5.501 9.024 6.761 9.048 ;
     RECT  6.613 2.208 6.901 2.712 ;
     RECT  6.541 3.84 6.901 7.128 ;
     RECT  6.865 12.528 6.949 12.552 ;
     RECT  6.901 2.208 6.997 7.128 ;
     RECT  6.659 14.832 7.189 15.096 ;
     RECT  6.997 1.728 7.261 7.128 ;
     RECT  7.141 8.544 7.261 8.568 ;
     RECT  6.949 11.952 7.621 12.552 ;
     RECT  7.189 14.832 7.715 15.432 ;
     RECT  7.261 1.728 7.808 8.568 ;
     RECT  7.621 11.664 7.808 12.552 ;
     RECT  7.715 14.832 7.808 15.288 ;
     RECT  7.808 1.728 7.955 15.288 ;
     RECT  7.955 1.728 8.104 15.24 ;
     RECT  8.104 13.68 8.237 15.24 ;
     RECT  8.005 0.288 8.243 0.312 ;
     RECT  8.237 13.68 8.281 15.144 ;
     RECT  8.104 11.664 8.381 11.976 ;
     RECT  8.281 13.68 8.921 15.096 ;
     RECT  8.381 11.664 9.137 11.688 ;
     RECT  8.104 1.728 9.205 7.992 ;
     RECT  8.921 13.68 9.325 13.704 ;
     RECT  9.205 1.728 9.353 8.04 ;
     RECT  9.253 0.192 9.395 0.216 ;
     RECT  9.308 9.024 9.395 9.048 ;
     RECT  9.353 1.728 9.425 3.48 ;
     RECT  9.349 10.464 9.433 10.488 ;
     RECT  9.353 4.512 9.529 8.04 ;
     RECT  9.425 1.728 9.821 3.048 ;
     RECT  10.105 12.384 10.177 12.408 ;
     RECT  8.921 14.832 10.261 15.096 ;
     RECT  9.877 16.56 10.261 16.584 ;
     RECT  9.541 0.528 10.357 0.552 ;
     RECT  10.261 14.832 10.361 16.68 ;
     RECT  10.357 0.192 10.397 0.552 ;
     RECT  10.361 16.56 10.403 16.68 ;
     RECT  9.821 2.016 10.505 3.048 ;
     RECT  10.505 2.148 10.508 3.048 ;
     RECT  9.529 4.512 10.508 8.568 ;
     RECT  10.177 11.712 10.508 12.408 ;
     RECT  10.361 14.832 10.508 15.432 ;
     RECT  10.508 2.148 10.612 15.432 ;
     RECT  10.612 2.418 10.685 15.432 ;
     RECT  10.397 0.192 10.739 0.216 ;
     RECT  10.403 16.56 10.757 16.584 ;
     RECT  10.685 2.418 10.804 14.862 ;
     RECT  10.804 11.712 10.865 11.928 ;
     RECT  10.804 5.424 12.78 5.448 ;
     RECT  10.865 11.904 12.78 11.928 ;
    LAYER M5 ;
     RECT  6.672 0.133 6.696 0.144 ;
     RECT  2.352 0.144 10.728 0.227 ;
     RECT  2.352 0.227 10.488 0.277 ;
     RECT  2.304 0.277 10.488 2.137 ;
     RECT  2.304 2.137 10.62 2.151 ;
     RECT  2.304 2.151 10.812 4.019 ;
     RECT  2.4 4.019 10.812 4.979 ;
     RECT  3.792 4.979 10.812 5.747 ;
     RECT  3.984 5.747 10.812 5.843 ;
     RECT  3.984 5.843 4.008 6.131 ;
     RECT  5.1 5.843 10.812 7.909 ;
     RECT  4.512 7.909 10.812 7.957 ;
     RECT  4.032 7.957 10.812 8.579 ;
     RECT  4.032 8.579 9.384 10.499 ;
     RECT  2.4 4.979 2.712 11.413 ;
     RECT  10.5 8.579 10.812 11.941 ;
     RECT  4.032 10.499 9.288 12.373 ;
     RECT  10.368 11.941 10.812 12.373 ;
     RECT  2.4 11.413 2.856 13.093 ;
     RECT  4.032 12.373 10.812 13.093 ;
     RECT  2.4 13.093 10.812 13.139 ;
     RECT  6.624 13.139 10.812 13.715 ;
     RECT  2.4 13.139 5.412 14.773 ;
     RECT  2.4 14.773 5.544 14.821 ;
     RECT  6.624 13.715 8.904 14.821 ;
     RECT  10.128 13.715 10.812 14.821 ;
     RECT  2.4 14.821 10.812 15.129 ;
     RECT  2.4 15.129 10.632 15.143 ;
     RECT  2.832 15.143 10.632 16.549 ;
     RECT  2.352 16.549 10.632 17.104 ;
  END
END dsfd_dvrly_70_SN
END LIBRARY
